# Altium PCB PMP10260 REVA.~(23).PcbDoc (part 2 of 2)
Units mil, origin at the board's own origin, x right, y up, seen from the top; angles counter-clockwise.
Board outline 5118.11 x 4724.41 mil, 4 copper layers (Top Layer, MidLayer1, MidLayer2, Bottom Layer), stack 63.8 mil thick; 168 components, 80 nets, 422 pads, 209 vias.
Unrouted connection lines stored in the file: 303.

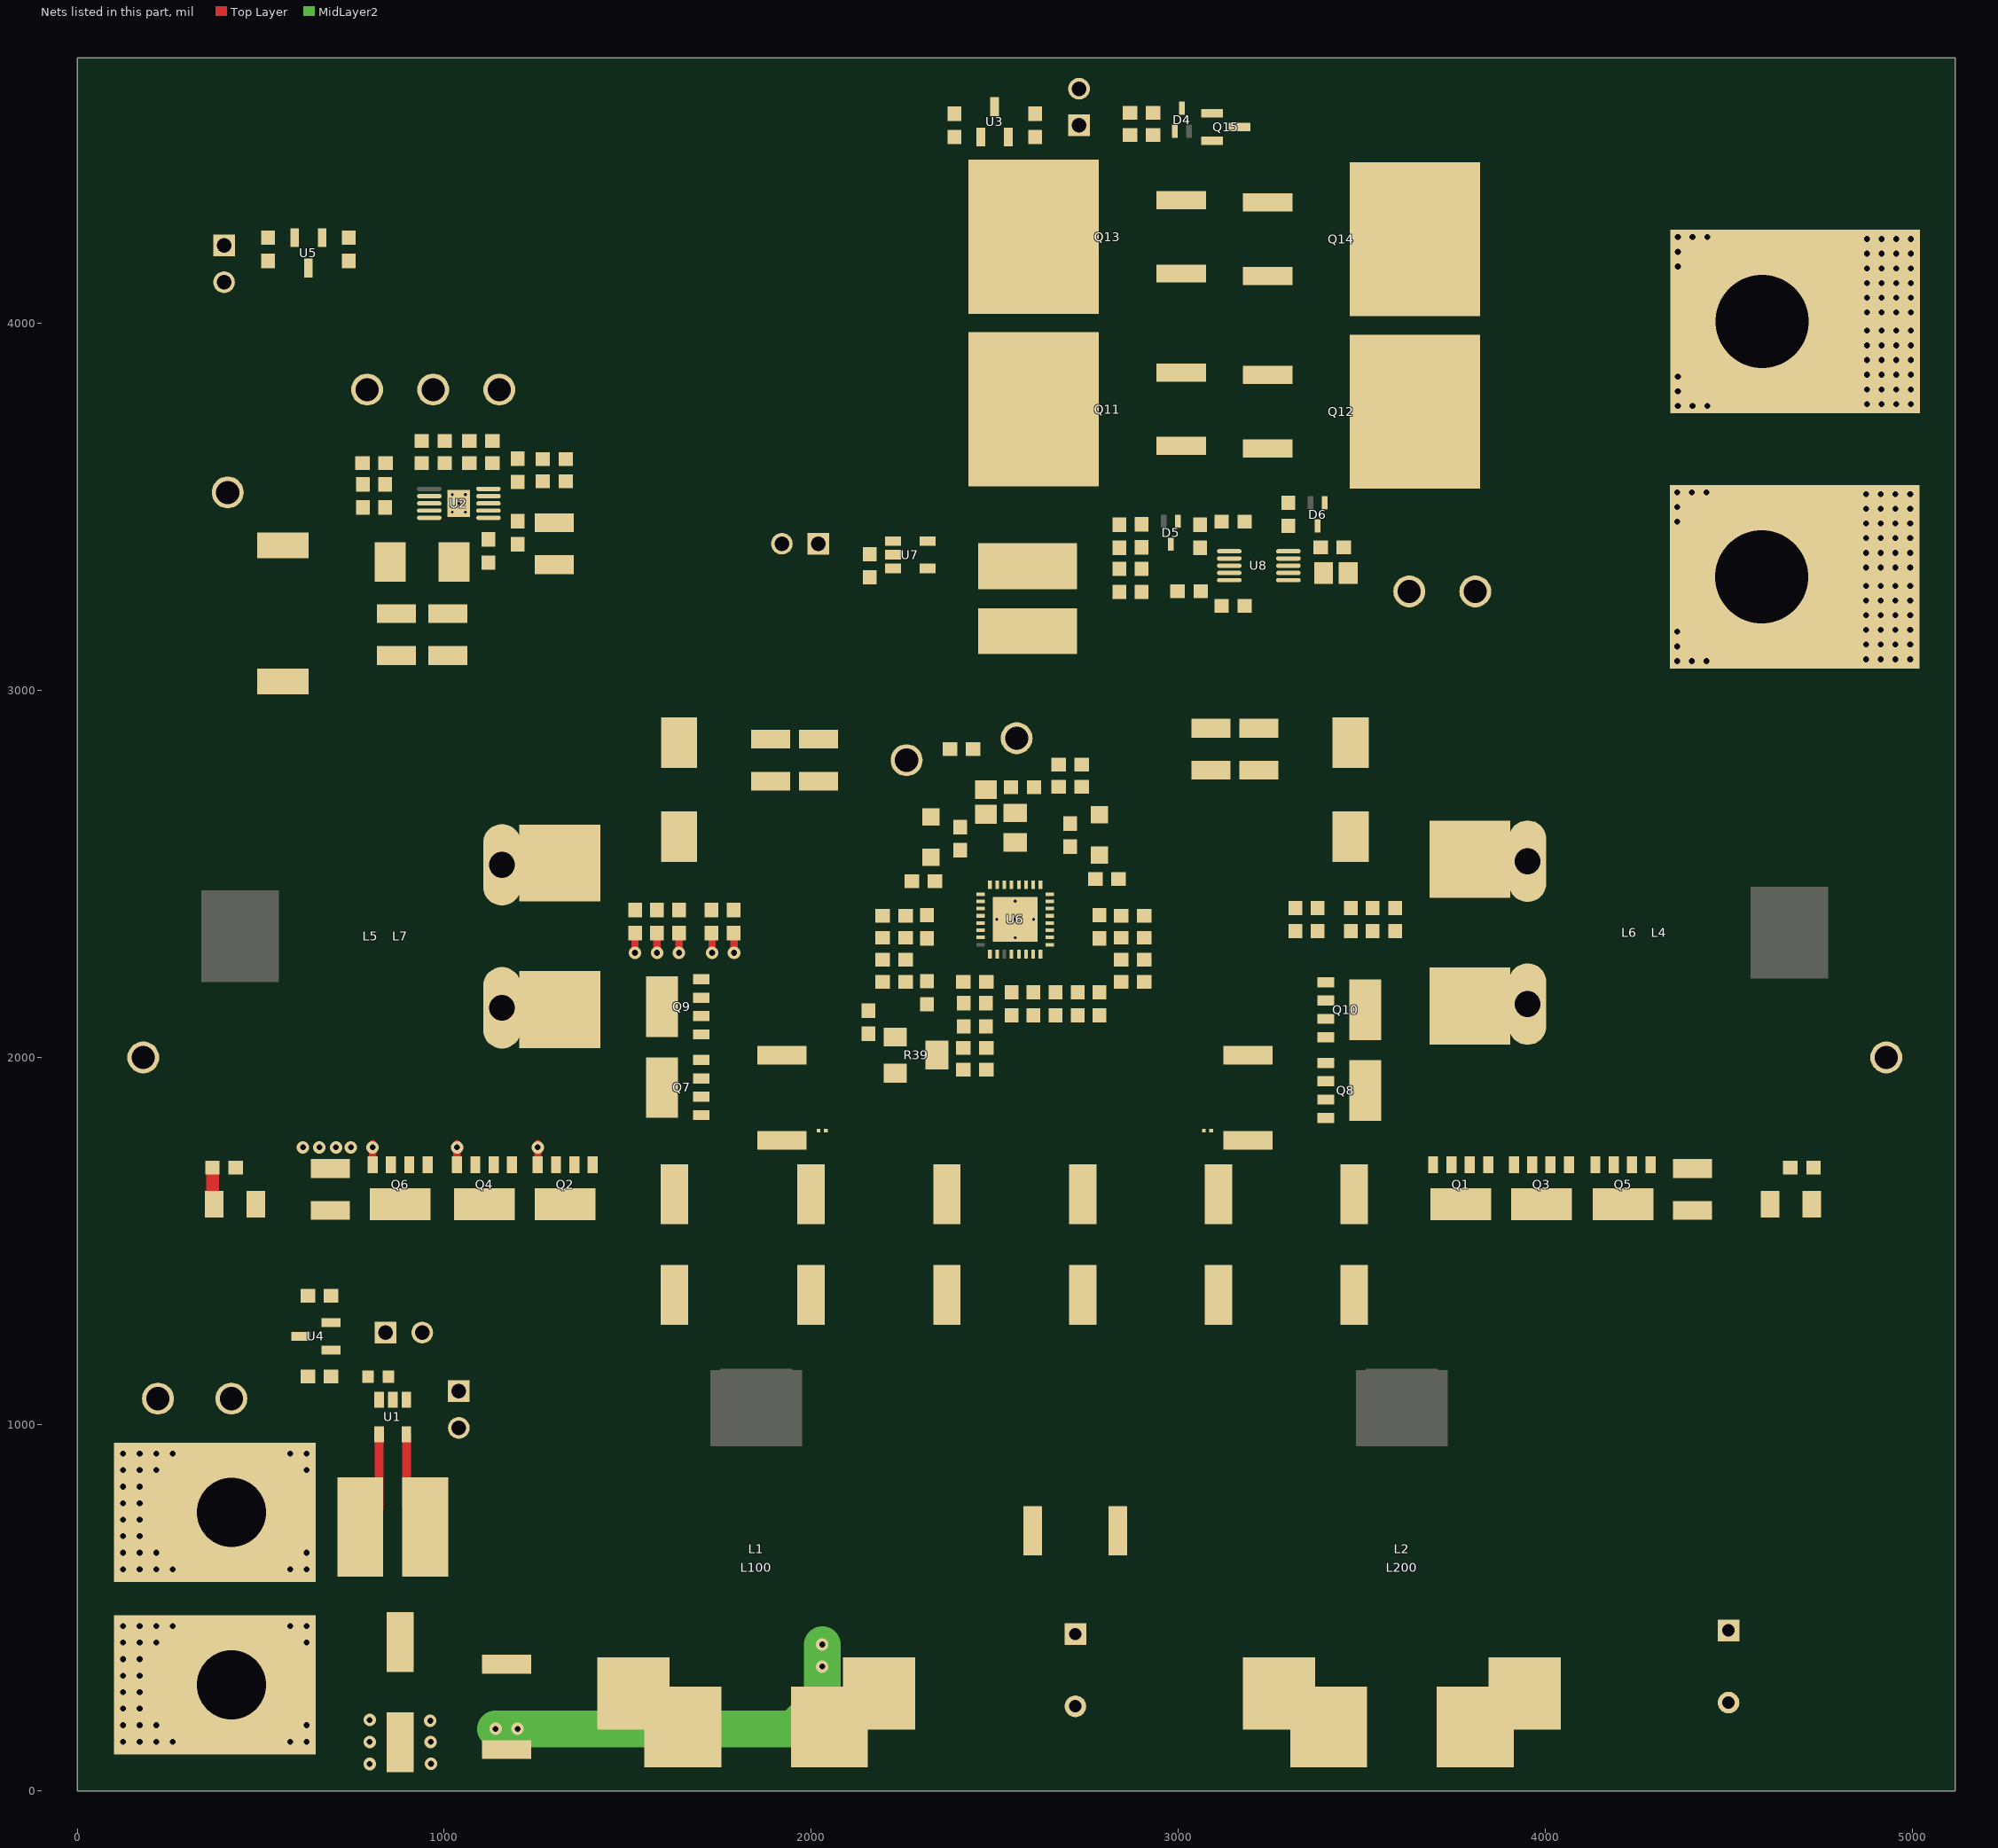
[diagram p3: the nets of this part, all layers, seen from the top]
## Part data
C1 C19 C20 C21 C22 C23 C24: "CAP, OS-CON, 33uF, 63V, +/-20%, 0.025 ohm, 8.0x11.9mm SMD"
C2 C3: "CAP, AL, 470uF, 63V, +/-20%, 0.043 ohm, TH"
C4 C9 C13 C15 C17 C41 C46 C51 C52: "CAP, CERM, 0.1uF, 50V, +/-10%, X7R, 0603"
C5 C25 C26: "CAP, CERM, 2.2uF, 100V, +/-10%, X7R, 1210"
C6: "CAP, CERM, 0.1uF, 100V, +/-10%, X7R, 0603"
C7 C8: "CAP, CERM, 22uF, 16V, +/-20%, X7R, 1210"
C10 C50: "CAP, CERM, 0.01uF, 50V, +/-10%, X7R, 0603"
C11: library part C1608C0G1H332J, "CAP, CERM, 4700pF, 50V, +/-5%, C0G/NP0, 0603"
C12: library part C1608X7R1H104K, "CAP, open, 0603"
C14 C16 C18 C28 C30 C31 C32: "CAP, CERM, 1uF, 25V, +/-10%, X7R, 0603"
C27: "CAP, CERM, 470pF, 50V, +/-5%, C0G/NP0, 0603"
C29: "CAP, CERM, 0.1uF, 100V, +/-10%, X7R, 0805"
C33 C38: "CAP, CERM, 2200pF, 50V, +/-10%, X7R, 0603"
C34 C37: "CAP, CERM, 10uF, 35V, +/-20%, X7R, 1206"
C35 C36: library part C3225X7R1H335M, "CAP, CERM, open, 1210"
C39 C40: library part 20SVP100M, "CAP, OS-CON, 390uF, 20V, +/-20%, 0.014 ohm, 8x10 SMD"
C42: "CAP, CERM, 0.47uF, 16V, +/-10%, X7R, 0603"
C43 C44 C45 C47: "CAP, CERM, 1000pF, 50V, +/-5%, C0G/NP0, 0603"
C48: "CAP, CERM, 100pF, 50V, +/-5%, C0G/NP0, 0603"
C49: "CAP, CERM, 0.033uF, 50V, +/-10%, X7R, 0603"
C53: "CAP, CERM, 0.27uF, 16V, +/-10%, X7R, 0805"
D1: "Diode, Schottky, 100V, 1A, SMB"
D2 D3: library part PMEG6010CEH,115, "Diode, Schottky, 60V, 1A, SOD-123F"
D4 D5 D6: "Diode, Switching, 85V, 0.215A, SOT-523"
J1 J2 J3 J4 J5: "Header, 100mil, 2x1, Tin, TH"
L1 L2: library part PG1096.252NL, "Inductor, Shielded E Core, Ferrite, 1.5uH, 47A, 0.00085 ohm, SMD"
L3: "Inductor, Shielded Drum Core, Ferrite, 100uH, 1.36A, 0.25 ohm, SMD"
L4 L5: library part SER29XX, "Inductor, open, TH"
L6 L7: "Inductor, Shielded E Core, Ferrite, 6.8uH, 30A, 0.00186 ohm, SMD"
L100 L200: library part SER2918H-332KL, "Inductor, Shielded E Core, Ferrite, 3.3uH, 28A, 0.0026 ohm, SMD"
Logo1: library part TI_Logo, "Texas Instrument Corporate Signature"
NT1 NT2: "Single point connection between nets."
Q1 Q2 Q3 Q4 Q5 Q6 Q7 Q8 Q9 Q10: "MOSFET, N-CH, 60V, 100A, SOT669"
Q11 Q12 Q13 Q14: library part IPB100N10S3-05, "MOSFET, N-CH, 40V, 120A, DDPAK"
Q15: library part "MMBT2222A, Fairchild Semiconductor", "Transistor, NPN, 40V, 0.15A, SOT-23"
R1 R2: "RES, 0.2 ohm, 1%, 2W, 2512"
R3: library part CSS2725FTL500, "RES, 0.001 ohm, 1%, 4W, RES_2725"
R4 R35: "RES, 49.9 ohm, 1%, 0.1W, 0603"
R5: "RES, 178k ohm, 1%, 0.1W, 0603"
R6: "RES, 53.6k ohm, 1%, 0.1W, 0603"
R7: "RES, 10.2k ohm, 1%, 0.1W, 0603"
R8: "RES, 88.7k ohm, 1%, 0.1W, 0603"
R9: "RES, 49.9k ohm, 1%, 0.1W, 0603"
R10: "RES, 237k ohm, 1%, 0.1W, 0603"
R11: "RES, 75.0k ohm, 1%, 0.1W, 0603"
R12: "RES, 1.00 ohm, 1%, 0.125W, 0805"
R13: "RES, 5.76k ohm, 1%, 0.1W, 0603"
R14 R15 R16 R17 R18 R19 R20 R21 R25 R26: "RES, 2.2 ohm, 5%, 0.1W, 0603"
R22 R24: "RES, 10 ohm, 5%, 0.25W, 1206"
R23 R36: "RES, 0 ohm, 5%, 0.1W, 0603"
R27 R28 R32 R34: "RES, 100 ohm, 1%, 0.1W, 0603"
R29 R30: library part CSRN2512FKR200, "RES, 0.001ohm, 1%, 2W, 2512"
R31 R33: "RES, 249k ohm, 1%, 0.1W, 0603"
R37 R38: "RES, 20.0k ohm, 1%, 0.1W, 0603"
R39: "TRIMMER, 10K, 0.25W, SMD"
R40: "RES, 1.62k ohm, 1%, 0.1W, 0603"
R41: "RES, 36.5k ohm, 1%, 0.1W, 0603"
R42: "RES, 3.01k ohm, 1%, 0.1W, 0603"
R43: "RES, 0.0005 ohm, 1%, 4W, RES_2725"
R44 R49 R52 R53: "RES, 10.0k ohm, 1%, 0.1W, 0603"
R45: "RES, 13.7k ohm, 1%, 0.1W, 0603"
R46 R47: "RES, 82.5k ohm, 1%, 0.1W, 0603"
R48: "RES, 1.00k ohm, 1%, 0.1W, 0603"
R50: "RES, 16.5k ohm, 1%, 0.1W, 0603"
R51: "RES, 11.0k ohm, 1%, 0.1W, 0603"
T1 T2: "Terminal 50A Lug"
T3 T4: "Terminal 90A Lug"
TP1 TP3 TP4 TP5 TP7 TP8 TP9 TP10 TP11 TP12: "Test Point, Multipurpose, Red, TH"
TP2 TP6: "Test Point, Multipurpose, Black, TH"
U1 U7: "CURRENT SHUNT MONITOR -16V to +80V Common-Mode Range, DBV0005A"
U2: "Buck Inverting Buck-Boost Step Down Regulator with 3.5 to 60 V Input and 0.8 to 58 V Output, -40 to 150 degC, 10-Pin MSOP-PowerPAD (DGQ), Green (RoHS & no Sb/Br)"
U3 U4 U5: "Single-Supply Centigrade Temperature Sensor, 3-pin SOT-23, Pb-Free"
U6: "LM5119/LM5119Q Wide Input Range Dual Synchronous Buck Controller, RTV0032A"
U8: "High-Side Protection Controller with Low Quiescent Current, 10-pin MSOP, Pb-Free"

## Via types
v1: diameter 32, hole 16, Top Layer to Bottom Layer, 172 vias
v2: diameter 34, hole 16, Top Layer to Bottom Layer, 22 vias
v3: diameter 19.68, hole 7.87, Top Layer to Bottom Layer, 10 vias
v4: diameter 200, hole 150, Top Layer to Bottom Layer, 5 vias

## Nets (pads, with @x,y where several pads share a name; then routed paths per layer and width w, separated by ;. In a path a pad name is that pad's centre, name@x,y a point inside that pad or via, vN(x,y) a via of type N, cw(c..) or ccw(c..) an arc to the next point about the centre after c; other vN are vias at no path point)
COMP: C48.1 R38.1 U6.10 U6.15
GND: C1.2 C2.2 C3.2 C4.2 C5.2 C6.2 C7.2 C8.2 C10.2 C11.2 C12.2 C13.2 C14.2 C15.2 C16.2 C17.2 C18.2 C19.2 C20.2 C21.2 C22.2 C23.2 C24.2 C25.2 C26.2 C27.2 C28.2 C29.2 C30.2 C34.2 C35.2 C36.2 C37.2 C39.2 C40.2 C41.1 C42.1 C45.2 C46.2 C47.2 C50.2 C51.2 C52.2 C53.2 D1.2 J1.2 J2.2 J3.2 J4.2 J5.2 NT1.2 NT2.1 R7.1 R9.1 R10.1 R13.1 R22.1 R24.1 R29.1 R30.1 R40.1 R41.1 R42.1 R44.1 R50.1 R51.1 T2.1 T4.1 TP2.1 TP6.1 U1.2 U2.9 U2.11 U3.3 U4.3 U5.3 U6.3 U6.12 U6.22 U6.33 U7.2 U8.6
  other v1: 125,135 170,135 215,135 260,135 580,135 625,135 125,180 170,180 215,180 625,180 125,225 170,225 125,270 170,270 125,315 170,315 125,360 170,360 125,405 170,405 215,405 625,405 125,450 170,450 215,450 260,450 580,450 625,450 4360,3080 4400,3080 4440,3080 4875,3085 4915,3085 4955,3085 4995,3085 4360,3120 4875,3125 4915,3125 4955,3125 4995,3125 4360,3160 4875,3165 4915,3165 4955,3165 4995,3165 4875,3205 4915,3205 4955,3205 4995,3205 4875,3245 4915,3245 4955,3245 4995,3245 4875,3285 4915,3285 4955,3285 4995,3285 4875,3335 4915,3335 4955,3335 4995,3335 4875,3375 4915,3375 4955,3375 4995,3375 4875,3415 4915,3415 4955,3415 4995,3415 4875,3455 4915,3455 4955,3455 4995,3455 4360,3460 4875,3495 4915,3495 4955,3495 4995,3495 4360,3500 4875,3535 4915,3535 4955,3535 4995,3535 4360,3540 4400,3540 4440,3540
  other v2: 796.88,74.36 964,75 796.88,134.36 963.12,134.36 962,192 796.88,194.36 615,1755 660,1755 705,1755 745.63,1755
  other v3: 2556.06,2326.06 2506.06,2376.06 2556.06,2376.06 2606.06,2376.06 2556.06,2426.06 1022.3,3486.35 1057.74,3486.35 1040.02,3509.97 1022.3,3533.59 1057.74,3533.59
NetC1_1: C1.1 L1.1 L100.1 R1.1 R3.2 U1.5 | length 274
  Top Layer w25: U1.5@897.41,972.75 897.41,771.18 R3.2@948.58,720
NetC2_1: C2.1 L1.2 L2.1 L100.2 L200.1 R1.2 R2.1 | length 1073.1
  MidLayer2 w100: v2(1140,170) 1950,170 2030,250 v2(2030,340) v2(2030,400)
  other v2: 1200,170
NetC9_1: C9.1 D1.1 L3.1 TP4.1 U2.10
NetC9_2: C9.2 U2.1
NetC10_1: C10.1 U2.4
NetC11_1: C11.1 R8.2
NetC12_1: C12.1 R8.1 U2.8
NetC14_1: C14.1 J2.1 U3.2
NetC16_1: C16.1 J3.1 U4.2
NetC18_1: C18.1 J4.1 U5.2
NetC28_1: C28.1 D2.2 U6.1
NetC29_1: C29.1 R12.2 U6.29
NetC31_1: C31.1 D2.1 U6.30
NetC31_2: C31.2 C38.1 L5.2 L7.1 Q2.1 Q2.2 Q2.3 Q4.1 Q4.2 Q4.3 Q6.1 Q6.2 Q6.3 Q7.5 Q9.5 R33.2 TP8.1 U6.32
NetC32_1: C32.1 D3.1 U6.27
NetC32_2: C32.2 C33.1 L4.1 L6.2 Q1.1 Q1.2 Q1.3 Q3.1 Q3.2 Q3.3 Q5.1 Q5.2 Q5.3 Q8.5 Q10.5 R31.2 TP7.1 U6.25
NetC33_2: C33.2 R22.2
NetC38_2: C38.2 R24.2 | length 101.8
  Top Layer w35: C38.2@368.5,1700 368.5,1604.41 R24.2@372.91,1600
NetC41_2: C41.2 U6.18
NetC42_2: C42.2 U6.14
NetC43_1: C43.1 R27.1 U6.20
NetC43_2: C43.2 R34.1 U6.21
NetC44_1: C44.1 R28.1 U6.5
NetC44_2: C44.2 R32.1 U6.4
NetC45_1: C45.1 R31.1 U6.19
NetC46_1: C46.1 U6.7
NetC47_1: C47.1 R33.1 U6.6
NetC48_2: C48.2 C49.2 R37.1 R39.1 R39.2 R40.2 U6.9
NetC49_1: C49.1 R38.2
NetC50_1: C50.1 D4.3 Q15.1 R44.2
NetC52_1: C52.1 D5.3 U8.2
NetC53_1: C53.1 U8.7
NetD4_1: D4.1 Q11.3 Q12.3 Q13.3 Q14.3 Q15.2
NetD5_1: D5.1 Q11.4 Q13.4 R43.2 R45.2 R46.2 R47.2 U7.5
NetD6_1: D6.1 Q11.1 Q12.1 Q13.1 Q14.1 Q15.3 R48.1
NetD6_3: D6.3 R48.2 U8.10
NetJ1_1: J1.1 U1.1
NetJ5_1: J5.1 U7.1
NetNT1_1: NT1.1 R34.2
NetNT2_2: NT2.2 R32.2
NetQ1_4: Q1.4 R16.2
NetQ2_4: Q2.4 R17.1 | length 111.3
  Top Layer w20: Q2.4@1254.84,1707.28 1255,1707.44 v2@1255,1765 ; v2(1640,2285) R17.1@1640,2338.5
  other v2: 1255,1755
NetQ3_4: Q3.4 R14.2
NetQ4_4: Q4.4 R15.1 | length 111.3
  Top Layer w20: Q4.4@1034.84,1707.28 1035,1707.44 v2@1035,1765 ; v2(1580,2285) R15.1@1580,2338.5
  other v2: 1035,1755
NetQ5_4: Q5.4 R18.2
NetQ6_4: Q6.4 R19.1 | length 111.3
  Top Layer w20: Q6.4@804.84,1707.28 805,1707.44 v2@805,1765 ; v2(1520,2285) R19.1@1520,2338.5
  other v2: 805,1755
NetQ7_1: Q7.1 Q7.2 Q7.3 Q9.1 Q9.2 Q9.3 R28.2 R30.2
NetQ7_4: Q7.4 R20.1 | length 52.2
  Top Layer w20: v2(1790,2285) R20.1@1790,2337.2
NetQ8_1: Q8.1 Q8.2 Q8.3 Q10.1 Q10.2 Q10.3 R27.2 R29.2
NetQ8_4: Q8.4 R21.2
NetQ9_4: Q9.4 R25.1 | length 52.2
  Top Layer w20: v2(1730,2285) R25.1@1730,2337.2
NetQ10_4: Q10.4 R26.2
NetQ12_4: Q12.4 Q14.4 R49.1 T3.1
  other v1: 4361.89,3775.55 4401.89,3775.55 4441.89,3775.55 4876.89,3780.55 4916.89,3780.55 4956.89,3780.55 4996.89,3780.55 4361.89,3815.55 4876.89,3820.55 4916.89,3820.55 4956.89,3820.55 4996.89,3820.55 4361.89,3855.55 4876.89,3860.55 4916.89,3860.55 4956.89,3860.55 4996.89,3860.55 4876.89,3900.55 4916.89,3900.55 4956.89,3900.55 4996.89,3900.55 4876.89,3940.55 4916.89,3940.55 4956.89,3940.55 4996.89,3940.55 4876.89,3980.55 4916.89,3980.55 4956.89,3980.55 4996.89,3980.55 4876.89,4030.55 4916.89,4030.55 4956.89,4030.55 4996.89,4030.55 4876.89,4070.55 4916.89,4070.55 4956.89,4070.55 4996.89,4070.55 4876.89,4110.55 4916.89,4110.55 4956.89,4110.55 4996.89,4110.55 4876.89,4150.55 4916.89,4150.55 4956.89,4150.55 4996.89,4150.55 4361.89,4155.55 4876.89,4190.55 4916.89,4190.55 4956.89,4190.55 4996.89,4190.55 4361.89,4195.55 4876.89,4230.55 4916.89,4230.55 4956.89,4230.55 4996.89,4230.55 4361.89,4235.55 4401.89,4235.55 4441.89,4235.55
NetR3_1: R3.1 T1.1 TP1.1 U1.4 | length 274
  Top Layer w25: R3.1@771.42,720 822.6,771.18 U1.4@822.6,972.75
  other v1: 125,605 170,605 215,605 260,605 580,605 625,605 125,650 170,650 215,650 625,650 125,695 170,695 125,740 170,740 125,785 170,785 125,830 170,830 125,875 170,875 215,875 625,875 125,920 170,920 215,920 260,920 580,920 625,920
NetR4_1: R4.1 R6.2 TP5.1
NetR5_1: R5.1 R9.2 U2.3
NetR6_1: R6.1 R7.2 U2.7
NetR10_2: R10.2 U2.5
NetR14_1: R14.1 R16.1 R18.1 U6.26
NetR15_2: R15.2 R17.2 R19.2 U6.31
NetR20_2: R20.2 R25.2 U6.2
NetR21_1: R21.1 R26.1 U6.23
NetR23_1: R23.1 U6.16
NetR35_1: R35.1 R37.2 TP10.1
NetR36_2: R36.2 U6.17
NetR39_3: R39.3 R42.2
NetR41_2: R41.2 U6.13
NetR45_1: R45.1 U8.1
NetR46_1: R46.1 R50.2 U8.4
NetR47_1: R47.1 R51.2 U8.3
NetR49_2: R49.2 U8.9
NetR52_2: R52.2 TP11.1 U8.8
NetR53_2: R53.2 TP12.1 U8.5
UVLO: C27.1 R11.1 R13.2 U6.28
VCC2: C30.1 D3.2 R23.2 R36.1 U6.24
VCC_5V: C4.1 C7.1 C8.1 C13.1 C15.1 C17.1 C51.1 L3.2 R4.2 R52.1 R53.1 TP3.1 U1.3 U3.1 U4.1 U5.1 U7.3
VIN: C3.1 C5.1 C6.1 C19.1 C20.1 C21.1 C22.1 C23.1 C24.1 C25.1 C26.1 L2.2 L200.2 Q1.5 Q2.5 Q3.5 Q4.5 Q5.5 Q6.5 R2.2 R5.2 R11.2 R12.1 U2.2
VOUT: C34.1 C35.1 C36.1 C37.1 C39.1 C40.1 L4.2 L5.1 L6.1 L7.2 R35.2 R43.1 TP9.1 U7.4
pads on no net: D4.2 D5.2 D6.2 L1.3 L2.3 L4.3 L5.3 L6.3 L7.3 L100.3 L200.3 U2.6 U6.8 U6.11
copper on no net:
  other v4: 410,1360 4800,1360 2680,1900 1240,4510 4140,4510

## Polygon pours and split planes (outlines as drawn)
VIN on Top Layer "Top Layer-No Net 4" (solid, pour order 10): 3650,-2.5 5118.11,-2.5 5118.11,1500 5120.61,1502.5 5120.61,1540 4570,1540 4510,1600 4470,1640 3590,1640 3580,1640 3560,1620 3560,1550 3560,1530 3540,1510 3340,1510 1640,1510 1610,1510 1570,1510 1550,1530 1550,1610 1520,1640 1340,1640 610,1640 580,1610 580,1530 580,1490 580,1480 600,1460 740,1460 840,1360 940,1360 960,1360 1140,1180 1148.19,1171.81 2010,1171.81 2018.19,1171.81 2050,1140 2050,1030 2110,970 2120,960 2650,960 2670,960 2750,880 2780,850 2780,700 2780,653.23 2793.23,640 2910,640 3370,640 3550,460 3630,380 3630,350 3630,0
NetC2_1 on Top Layer "Top Layer-No Net 3" (solid, pour order 8): 1930,30 1930,810 1950,830 1960,840 1960,850 2555.94,850 2630,775.94 2630,644.06 2630,610 2660,580 3310,580 3340,580 3570,350 3570,0 1932.5,0 1930,-2.5
NetC2_1 on Top Layer "Top Layer-No Net 2" (solid, pour order 6): 1093.23,190 1093.23,78.43 1246.77,78.43 1246.77,190
NetC1_1 on Top Layer "Top Layer-No Net 1" (solid, pour order 4): 890,851.89 890,340 900,330 950,330 980,330 1070,240 1270,240 1290,220 1290,0 1830,0 1830,550 1830,830 1810,850 1808.11,851.89 960,851.89 900,851.89
NetR3_1 on Top Layer "Top Layer-No Net" (solid, pour order 2): 100,950 830,950 830,570 450,570 100,570

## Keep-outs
Keep-Out Layer:
  lines w5: -2.5,0 ccw(c0,0) 0,-2.5 ; -2.5,0 ccw(c0,0) 0,-2.5 ; -2.5,0 -2.5,4724.41 ; -2.5,4724.41 cw(c0,4724.41) 0,4726.91 ; -2.5,4724.41 cw(c0,4724.41) 0,4726.91 ; 0,-2.5 5118.11,-2.5 ; 0,4726.91 5118.11,4726.91 ; 5118.11,-2.5 ccw(c5118.11,0) 5120.61,0 ; 5118.11,-2.5 ccw(c5118.11,0) 5120.61,0 ; 5118.11,4726.91 cw(c5118.11,4724.41) 5120.61,4724.41 ; 5118.11,4726.91 cw(c5118.11,4724.41) 5120.61,4724.41 ; 5120.61,0 5120.61,4724.41
  lines w7.01: 0,0 0,4724.41 5118.11,4724.41 5118.11,0 0,0
  text ".Layer_Name" at 577,-858.49 h60

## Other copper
Top Layer:
  text ".Layer_Name" at 577,-858.49 h60
Bottom Layer:
  text ".Layer_Name" at 577,-858.49 h60

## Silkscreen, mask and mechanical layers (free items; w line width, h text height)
Top Overlay:
  text ".PRJ_Number" at 4300,830 h60
  text ".PCB_Rev" at 4890,830 h60
  text ".Layer_Name" at 577,-858.49 h60
Bottom Overlay:
  text ".Layer_Name" at 577,-858.49 h60
Top Paste:
  text ".Layer_Name" at 577,-858.49 h60
Bottom Paste:
  text ".Layer_Name" at 577,-858.49 h60
Top Solder:
  text ".Layer_Name" at 577,-858.49 h60
  text ".Layer_Name" at 577,-858.49 h60
Bottom Solder:
  text ".Layer_Name" at 577,-858.49 h60
Drill Guide:
  text ".Layer_Name" at 577,-858.49 h60
M1 Board Outline:
  the board outline again, w7.01
  text ".Layer_Name" at 577,-858.49 h60
M2 Board Dimensions:
  rectangle: 124.5,-410.5 499.5,-285.5
  rectangle: -0.5,-285.5 124.5,-160.5
  lines w7: -0.5,-285.5 999.5,-285.5 ; 124.5,-410.5 124.5,-160.5 ; 249.5,-410.5 249.5,-160.5 ; 499.5,-410.5 499.5,-160.5 ; 749.5,-410.5 749.5,-160.5 ; -0.5,-410.5 -0.5,-160.5 999.5,-160.5 999.5,-410.5 -0.5,-410.5
  lines w10: -0.5,-475.5 -0.5,-455.5 ; 59.5,-485.5 -0.5,-465.5 ; 59.5,-445.5 -0.5,-465.5 ; 223.58,-465.5 -0.5,-465.5 ; 775.42,-465.5 999.5,-465.5 ; 939.5,-485.5 999.5,-465.5 ; 939.5,-445.5 999.5,-465.5 ; 999.5,-475.5 999.5,-455.5
  text "1000 (mil)" at 233.58,-501.49 h60
  text ".Layer_Name" at 577,-858.49 h60
M3 3D STEP Top:
  text ".Layer_Name" at 577,-858.49 h60
M4 3D STEP Bottom:
  text ".Layer_Name" at 577,-858.49 h60
M5 Assembly Top:
  lines w10: -292,-930.17 6308,-930.17 ; -292,-726.83 6310,-726.83 ; -292,-523.5 -292,-1133.5 3713,-1133.5 6310,-1133.5 6310,-523.5 -291.5,-523.5 -291.5,-1133.5 1284,-1133.5 ; 2173,-1133.5 2173,-523.5 ; 3440,-726.83 3440,-523.5 ; 4280,-726.83 4280,-523.5 ; 4902,-1140 4902,-937.17
  text "COMPONENTS MARKED 'DNP' SHOULD NOT BE POPULATED." at 1153.5,-318.5 h60
  text "ASSEMBLY VARIANT:" at 1153,-434 h60
  text ".VariantName" at 2189,-434 h60
  text "PCB VIEWED FROM TOP SIDE" at -228.5,-655.67 h60
  text "BOARD #:" at 2248,-655.67 h60
  text ".PRJ_Number" at 2793.5,-655.67 h60
  text "REV:" at 3638,-655.67 h60
  text ".PCB_Rev" at 3929.5,-655.67 h60
  text "SVN REV:" at 4476,-655.67 h60
  text ".VersionControl_RevNumber" at 4982,-655.67 h60
  text "IGNORE ->" at -228.5,-858.49 h60
  text "PLOT NAME =" at -228.5,-1064.34 h60
  text ".plot_File_Name" at 577,-1064.34 h60
  text "GENERATED    :" at 2250,-1064.34 h60
  text ".Print_Date" at 3119.5,-1064.34 h60
  text ".Print_Time" at 3848.5,-1064.34 h60
  text "TEXAS INSTRUMENTS" at 5113,-1064.34 h60
M6 Assembly Bottom:
  lines w10: -292.5,-727.33 6309.5,-727.33 ; -290.5,-930.67 6309.5,-930.67 ; 1115.5,-1140.5 1115.5,-937.67 ; 1737.5,-727.33 1737.5,-524 ; 2577.5,-727.33 2577.5,-524 ; 3844.5,-1134 3844.5,-524 ; 4733.5,-1134 6309,-1134 6309,-524 -292.5,-524 -292.5,-1134 2304.5,-1134 6309.5,-1134 6309.5,-524
  text "COMPONENTS MARKED 'DNP' SHOULD NOT BE POPULATED." at 6102,-318 h60
  text ".VariantName" at 5058,-434 h60
  text "ASSEMBLY VARIANT:" at 6097,-434 h60
  text ".VersionControl_RevNumber" at 1035.5,-656.17 h60
  text "SVN REV:" at 1541.5,-656.17 h60
  text ".PCB_Rev" at 2088,-656.17 h60
  text "REV:" at 2379.5,-656.17 h60
  text ".PRJ_Number" at 3224,-656.17 h60
  text "BOARD #:" at 3769.5,-656.17 h60
  text "PCB VIEWED FROM BOTTOM SIDE" at 6246,-656.17 h60
  text "IGNORE ->" at 2547.85,-858.49 h60
  text "TEXAS INSTRUMENTS" at 904.5,-1064.84 h60
  text ".Print_Time" at 2169,-1064.84 h60
  text ".Print_Date" at 2898,-1064.84 h60
  text "GENERATED    :" at 3767.5,-1064.84 h60
  text ".plot_File_Name" at 5440.5,-1064.84 h60
  text "PLOT NAME =" at 6246,-1064.84 h60
M9 Title Sheet:
  drawing of 57 lines, arcs and shapes, not listed
  text "1" at 739.84,8036.5 h70
  text "2" at 3235.5,8036.5 h70
  text "3" at 5724.84,8036.5 h70
  text "4" at 8231.51,8036.5 h70
  text "5" at 10730.5,8036.5 h70
  text "6" at 13235.5,8036.5 h70
  text "A" at -416.5,6893.5 h70
  text "A" at 14383.5,6893.5 h70
  text "B" at -416.5,4513.5 h70
  text "B" at 14383.5,4513.5 h70
  text "C" at -416.5,2138.5 h70
  text "C" at 15285.5,1822.5 h70
  text "PROJECT TITLE:" at 11343.5,277.5 h45
  text ".PRJ_Title" at 11393.5,144.17 h70
  text "DESIGNED FOR:" at 11343.5,-23.5 h45
  text ".PRJ_Customer" at 11393.5,-163.5 h70
  text "D" at -416.5,-231.5 h70
  text "D" at 14383.5,-231.5 h70
  text "FILE NAME:" at 11343.5,-323.5 h45
  text ".PCB_File_Name_No_Path" at 11393.5,-443.5 h70
  text "Texas Instruments (TI) and/or its licensors do not warrant the accuracy or completeness of this specification" at 6374,-605.34 h45
  text "ENGINEER:" at 11343.5,-613.5 h45
  text "LAYOUT BY:" at 12848.5,-613.5 h45
  text "or any information contained therein. TI and/or its licensors do not warrant that this design will meet" at 6329.01,-718 h45
  text ".PRJ_Engineer" at 11393.5,-768.49 h70
  text ".PCB_Layout" at 12899,-768.49 h70
  text "the specifications, will be suitable for your application or fit for any particular purpose, or will operate in" at 6329.01,-830.67 h45
  text ".Layer_Name" at 577,-858.49 h60
  text "ALTIUM DESIGNER VERSION:" at 12848.5,-923.5 h45
  text "an implementation. TI and/or its licensors do not warrant that the design is production worthy. You should" at 6329.01,-943.33 h45
  text "completely validate and test your design implementation to confirm the system functionality for your application." at 6374,-1056 h45
  text ".print_Scale" at 11393.5,-1056.83 h70
  text ".Application_BuildNumber" at 12899,-1056.83 h70
  text "1" at 739.84,-1263.5 h70
  text "2" at 3235.5,-1263.5 h70
  text "3" at 5724.84,-1263.5 h70
  text "4" at 8231.51,-1263.5 h70
  text "5" at 10730.5,-1263.5 h70
  text "6" at 13235.5,-1263.5 h70
M10 Fab Notes:
  drawing of 212 lines, arcs and shapes, not listed
  text "DESIGN INFORMATION" at 12381.02,6810 h60
  text "(REFER ALSO ARRAY/PANEL PROFILING INFORMATION)" at 12019.46,6648.29 h60
  text "BOARD SIZE" at 11333.46,6644 h60
  text "3450MIL" at 11795.78,6516.18 h60
  text "X" at 12301.46,6516.18 h60
  text "4950MIL" at 12532.78,6516.18 h60
  text "Number of Layers :" at 11736.46,6319 h60
  text "2" at 12831.27,6309 h60
  text "MIN. TRACK WIDTH:" at 11736.46,6180 h60
  text "8" at 12832.7,6180 h60
  text "MIL" at 12987.46,6180 h60
  text "MIN. CLEARANCE:" at 11736.46,6048 h60
  text "8" at 12832.7,6048 h60
  text "MIL" at 12987.46,6048 h60
  text "MIN. VIA PAD SIZE:" at 11736.46,5916 h60
  text "24" at 12802.71,5916 h60
  text "MIL" at 12987.46,5916 h60
  text "0.05mm (2MIL)" at 12431.46,5774.29 h60
  text "MINIMUM ANNULAR RING" at 11407.23,5770 h60
  text "EXTERNAL" at 13139.46,5770 h60
  text "PER" at 11607.23,5652 h60
  text "IPC-D-275 CLASS 2 LEVEL C" at 11827.23,5652 h60
  text "MIL, HOLES" at 13315.46,5539.71 h60
  text "+/-" at 12923,5539 h60
  text "+/-" at 13777,5539 h60
  text "REGISTRATION TOLERANCES:" at 11407.23,5534 h60
  text "METAL" at 12607,5534 h60
  text "5" at 13183.2,5534 h60
  text "3" at 14016.2,5534 h60
  text "MIL" at 14132.46,5534 h60
  text "MATERIAL:" at 11332.46,5324.54 h60
  text "FR-4 High Tg" at 12318.9,5184.21 h60
  text "FR-408" at 11753.46,5175.64 h60
  text "X" at 12165.46,5175.64 h60
  text "OTHER" at 13241.46,5175.64 h60
  text "62 MIL (1.6mm) +/-10%" at 12073.56,5012.92 h60
  text "THICKNESS:" at 11407.23,5008.64 h60
  text "X" at 11945.4,5008.64 h60
  text "OTHER" at 13358.46,5008.64 h60
  text "TOLERANCE:" at 11407.23,4850.64 h60
  text "X" at 12246.53,4850.64 h60
  text "ANSI IPC-6012 TYPE 3 CLASS 2" at 12433.48,4850.64 h60
  text "OTHER +/-" at 12433.46,4694.64 h60
  text "BOW & TWIST:" at 11407.23,4537.64 h60
  text "X" at 12246.53,4537.64 h60
  text "ANSI IPC-6012 TYPE 3 CLASS 2" at 12433.48,4537.64 h60
  text "OTHER +/-" at 12433.46,4379.13 h60
  text "COPPER THICKNESS (FINISHED):" at 11332.46,4243.64 h60
  text "1.4MIL (1oz)" at 12212.46,4090.92 h60
  text "2MIL (1.4oz)" at 12979.46,4090.92 h60
  text "2.8MIL (2oz)" at 13706.46,4090.92 h60
  text "OUTER:" at 11689.46,4086.64 h60
  text "X" at 12084,4086 h60
  text "1.4MIL (1oz)" at 12212.46,3933.92 h60
  text "2.8MIL (2oz)" at 12979.46,3933.92 h60
  text "N/A" at 13706,3934.29 h60
  text "INNER SIGNAL:" at 11400.38,3929.64 h60
  text "X" at 12085.42,3929.64 h60
  text "DRILLING:" at 12234.46,3474.64 h60
  text "REFERENCE:" at 12309.23,3357.64 h60
  text "X" at 12957.46,3357.64 h60
  text "AS SHOWN" at 13144.46,3357.64 h60
  text "X" at 13858.46,3357.64 h60
  text "NC_DRILL FILES" at 13995.46,3357.64 h60
  text "PTH MIN COPPER THICKNESS:" at 12309.23,3199.64 h60
  text "X" at 13659.46,3199.64 h60
  text "1MIL" at 13796.46,3199.64 h60
  text "OTHER" at 14293.46,3199.64 h60
  text "BOARD FINISH:" at 12234.46,3040.64 h60
  text "SILKSCREEN:" at 12389.68,2922.64 h60
  text "X" at 13338.46,2922.64 h60
  text "TOP" at 13464.46,2922.64 h60
  text "X" at 13848.46,2922.64 h60
  text "BOTTOM" at 13975.46,2922.64 h60
  text "SILKSCREEN COLOR:" at 12389.68,2755.64 h60
  text "X" at 13337.42,2755.64 h60
  text "WHITE" at 13464.46,2755.64 h60
  text "OTHER" at 13975.46,2755.64 h60
  text "SOLDER RESIST COLOR:" at 12389.68,2585.64 h60
  text "X" at 12957.42,2426.44 h60
  text "GREEN" at 13084.46,2426.44 h60
  text "BLUE" at 13675.46,2426.44 h60
  text "OTHER" at 14213.46,2426.44 h60
  text "IMMERSION GOLD (ENIG)" at 13295.46,2237.92 h60
  text "ENEPIG" at 14633,2234.64 h60
  text "SURFACE FINISH:" at 12234.46,2233.64 h60
  text "X" at 13108.51,2233.64 h60
  text "IMM. TIN/SILVER OR EQUIV" at 12564,2076.64 h60
  text "OTHER" at 13995.46,2076.64 h60
  text "N.C. ROUTE" at 12393.46,2057.64 h60
  text "X" at 13072.46,2057.64 h60
  text "V. SCORE" at 13259.46,2057.64 h60
  text "CERTIFICATION:" at 11332.46,1920.64 h60
  text "MATERIALS AND WORKMANSHIP FOR ALL PCBS" at 12057.46,1920.64 h60
  text "ARRAY/PANEL:" at 12234.46,1897.64 h60
  text "CUT AND TRIM PER MECH LAYER 1" at 13295.46,1893.35 h60
  text "TO MEET OR EXCEED THE REQUIREMENTS OF:" at 12057.46,1822.64 h60
  text "X" at 11683.96,1686.13 h60
  text "ANSI IPC-A-600F CLASS ->" at 11822.96,1686.13 h60
  text "X" at 13462.02,1686.13 h60
  text "2" at 13580.96,1686.14 h60
  text "1" at 13265.96,1684.64 h60
  text "3" at 13934.96,1684.64 h60
  text "X" at 11686.02,1526.64 h60
  text "UL 94V-0" at 11822.96,1526.64 h60
  text "X" at 12498.02,1526.64 h60
  text "RoHS" at 12634.96,1526.64 h60
  text "OTHER" at 13279.36,1526.64 h60
  text "PER ORDER" at 13676.42,1526.64 h60
  text "ADDITIONAL REQUIREMENTS:" at 11332.46,1385.64 h60
  text "MICROSECTION:" at 11407.23,1270.64 h60
  text "YES" at 12312.96,1270.64 h60
  text "REQUIRED" at 13174.46,1114.49 h60
  text "BARE BOARD ELEC. TEST:" at 11407.23,1111.64 h60
  text "NONE" at 12712.96,1111.64 h60
  text "X" at 13047.46,1111.64 h60
  text "PER ORDER" at 13766.46,1111.64 h60
  text "MANUFACTURER'S UL:" at 11407.23,954.64 h60
  text "RAIL" at 12572.96,950.35 h60
  text "METAL" at 13064.77,950.35 h60
  text "X" at 13440,950 h60
  text "SILK" at 13576.46,950.35 h60
  text ".Layer_Name" at 577,-858.49 h60
M11 Gerber Information:
  lines w10: -292,-930.17 6308,-930.17 ; -292,-726.83 6310,-726.83 ; -292,-523.5 -292,-1133.5 3713,-1133.5 6310,-1133.5 6310,-523.5 -291.5,-523.5 -291.5,-1133.5 1284,-1133.5 ; 2173,-1133.5 2173,-523.5 ; 3440,-726.83 3440,-523.5 ; 4280,-726.83 4280,-523.5 ; 4902,-1140 4902,-937.17
  text "ALL ARTWORK VIEWED FROM TOP SIDE" at -228.5,-655.67 h60
  text "BOARD #:" at 2248,-655.67 h60
  text ".PRJ_Number" at 2793.5,-655.67 h60
  text "REV:" at 3638,-655.67 h60
  text ".PCB_Rev" at 3929.5,-655.67 h60
  text "SVN REV:" at 4476,-655.67 h60
  text ".VersionControl_RevNumber" at 4982,-655.67 h60
  text "LAYER NAME =" at -228.5,-858.49 h60
  text "PLOT NAME =" at -228.5,-1064.34 h60
  text ".plot_File_Name" at 577,-1064.34 h60
  text "GENERATED    :" at 2250,-1064.34 h60
  text ".Print_Date" at 3119.5,-1064.34 h60
  text ".Print_Time" at 3848.5,-1064.34 h60
  text "TEXAS INSTRUMENTS" at 5113,-1064.34 h60
M12 Stackup:
  lines w6: 11360,7690.5 14220,7690.5 ; 11360,7803.1 14220,7803.1 ; 11300,6966 ccw(c11336,6966) 11336,6930 14244,6930 ccw(c14244,6966) 14280,6966 14280,7904 ccw(c14244,7904) 14244,7940 11336,7940 ccw(c11336,7904) 11300,7904 11300,6966
  text "Layer Stack Up Detail for: PMP10260 REVA.PcbDoc" at 11360,7832.95 h52
  text "Layer" at 11360,7761.1 h26
  text "Gerber" at 12361.14,7761.1 h26
  text "Copper" at 13016.52,7761.1 h26
  text "Dielectric" at 13714.35,7761.1 h26
  text "Name" at 11360,7709.1 h26
  text "Document" at 12361.14,7709.1 h26
  text "Thickness" at 13016.52,7709.1 h26
  text "Material" at 13714.35,7709.1 h26
  text "Top Solder Mask" at 11360,7634.9 h36
  text "(.GTS)" at 12361.14,7634.9 h36
  text "Solder Resist" at 13714.35,7634.9 h36
  text "Top Layer" at 11360,7529.69 h36
  text "(.GTL)" at 12361.14,7529.69 h36
  text "2.8mil" at 13016.52,7529.69 h36
  text "FR-4" at 13714.35,7477.08 h36
  text "MidLayer1" at 11360,7424.48 h36
  text "(.G1)" at 12361.14,7424.48 h36
  text "2.8mil" at 13016.52,7424.48 h36
  text "FR-4" at 13714.35,7371.88 h36
  text "MidLayer2" at 11360,7319.27 h36
  text "(.G2)" at 12361.14,7319.27 h36
  text "2.8mil" at 13016.52,7319.27 h36
  text "FR-4" at 13714.35,7266.67 h36
  text "Bottom Layer" at 11360,7214.06 h36
  text "(.GBL)" at 12361.14,7214.06 h36
  text "2.8mil" at 13016.52,7214.06 h36
  text "Bottom Solder Mask" at 11360,7108.85 h36
  text "(.GBS)" at 12361.14,7108.85 h36
  text "Solder Resist" at 13714.35,7108.85 h36
  text ".Layer_Name" at 577,-858.49 h60
M13 Component Bodies Top:
  text ".Layer_Name" at 577,-858.49 h60
M14 Component Bodies Bottom:
  text ".Layer_Name" at 577,-858.49 h60
M15 Courtyards Top:
  text ".Layer_Name" at 577,-858.49 h60
M16 Courtyards Bottom:
  text ".Layer_Name" at 577,-858.49 h60
Drill Drawing:
  text "Drill Table" at 5930,60 h60
  text ".Layer_Name" at 577,-858.49 h60

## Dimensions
0,0 to 5118.11,0 on M2 Board Dimensions
0,0 to 0,4724.41 on M2 Board Dimensions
